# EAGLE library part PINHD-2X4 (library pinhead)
PIN HEADER

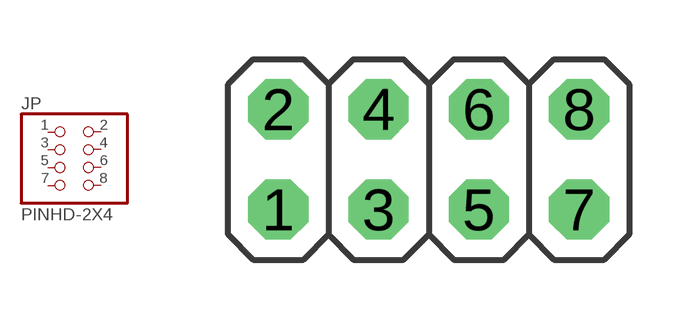
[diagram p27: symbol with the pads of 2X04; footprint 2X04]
Designator prefix JP

## PINHD-2X4  [2X04]
1  1  pas
2  2  pas
3  3  pas
4  4  pas
5  5  pas
6  6  pas
7  7  pas
8  8  pas

## Footprint 2X04 (pad centres in mm)
PIN HEADER
drill 1.016 octagon: 1 -3.81,-1.27; 2 -3.81,1.27; 3 -1.27,-1.27; 4 -1.27,1.27; 5 1.27,-1.27; 6 1.27,1.27; 7 3.81,-1.27; 8 3.81,1.27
